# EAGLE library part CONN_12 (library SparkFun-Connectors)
Multi connection point. Often used as Generic Header-pin footprint for 0.1 inch spaced/style header connections On any of the 0.1 inch spaced packages, you can populate with these: Break Away Headers - Straight (PRT-00116) Break Away Male Headers - Right Angle (PRT-00553) Female Headers (PRT-00115) Break Away Headers - Machine Pin (PRT-00117) Break Away Female Headers - Swiss Machine Pin (PRT-00743) For SCREWTERMINALS and SPRING TERMINALS visit here: Screw Terimnals on SparkFun.com (5mm/3.5mm/2.54mm spacing) This device is also useful as a general connection point to wire up your design to another part of your project. Our various solder wires solder well into these plated through hole pads. Hook-Up Wire - Assortment (Stranded, 22 AWG) (PRT-11375) Hook-Up Wire - Assortment (Solid Core, 22 AWG) (PRT-11367) View the entire wire category on our website here Special notes: Molex polarized connector foot print use with SKU : PRT-08231 with associated crimp pins and housings. 1MM SMD Version SKU: PRT-10208 NOTES ON THE VARIANTS LOCK and LOCK_LONGPADS... This footprint was designed to help hold the alignment of a through-hole component (i.e. 6-pin header) while soldering it into place. You may notice that each hole has been shifted either up or down by 0.005 of an inch from it's more standard position (which is a perfectly straight line). This slight alteration caused the pins (the squares in the middle) to touch the edges of the holes. Because they are alternating, it causes a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

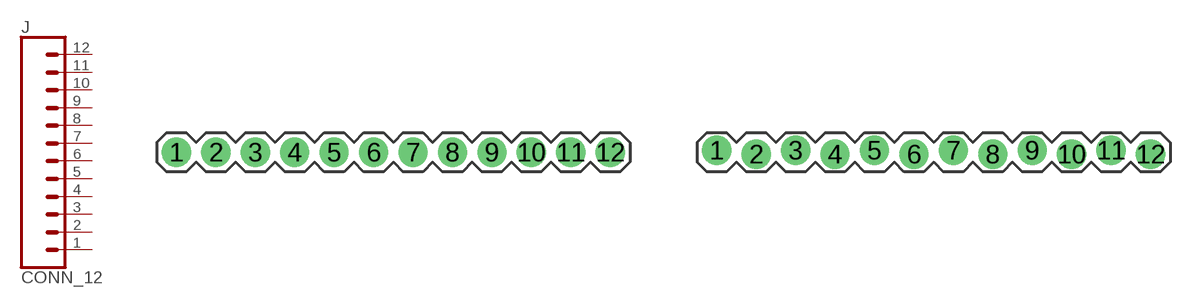
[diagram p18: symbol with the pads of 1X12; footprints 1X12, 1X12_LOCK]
Designator prefix J

## CONN_12  [1X12]
1  1  pas
2  2  pas
3  3  pas
4  4  pas
5  5  pas
6  6  pas
7  7  pas
8  8  pas
9  9  pas
10  10  pas
11  11  pas
12  12  pas

## CONN_12LOCK  [1X12_LOCK]
Pads as for 1X12

## CONN_12LOCK_LONGPADS  [1X12_LOCK_LONGPADS]
Pads as for 1X12

## CONN_12MACHINE-PIN_LOCK (PROD_ID: CONN-09704)  [1X12_MACHINE-PIN-HEADER_LOCK.004]
Pads as for 1X12

## CONN_12LONGPADS  [1X12_LONGPADS]
Pads as for 1X12

## CONN_12POGOPIN_HOLES_ONLY  [1X12_HOLES_ONLY]
Pads as for 1X12

## CONN_121X12_NO_SILK_KIT  [1X12_NO_SILK_KIT]
Pads as for 1X12

## CONN_12NO_SILK  [1X12_NO_SILK]
Pads as for 1X12

## CONN_12LOCK_NO_SILK  [1X12_LOCK_NO_SILK]
Pads as for 1X12

## CONN_12SM_SQ_NO_SILK  [1X12_SM_SQ_NOSILK]
Pads as for 1X12

## CONN_12CASTELLATED  [1X12_CASTELLATED]
1  1  pas
1B  1  pas
2  2  pas
2B  2  pas
3  3  pas
3B  3  pas
4  4  pas
4B  4  pas
5  5  pas
5B  5  pas
6  6  pas
6B  6  pas
7  7  pas
7B  7  pas
8  8  pas
8B  8  pas
9  9  pas
9B  9  pas
10  10  pas
10B  10  pas
11  11  pas
11B  11  pas
12  12  pas
12B  12  pas

## CONN_12SMD (PROD_ID: CONN-15197)  [1X12_SMD]
Pads as for 1X12

## CONN_12SMD_ALT (PROD_ID: CONN-15197)  [1X12_SMD_ALT]
Pads as for 1X12

## CONN_12SMD_COMBINED (PROD_ID: CONN-15197)  [1X12_SMD_COMBINED]
Pads as for 1X12

## CONN_12SMD_COMNINED_NC (PROD_ID: CONN-15197)  [1X12_SMD_COMBINED_NC]
1  1  pas
1@2  1  pas
2  2  pas
2@2  2  pas
3  3  pas
3@2  3  pas
4  4  pas
4@2  4  pas
5  5  pas
5@2  5  pas
6  6  pas
6@2  6  pas
7  7  pas
7@2  7  pas
8  8  pas
8@2  8  pas
9  9  pas
9@2  9  pas
10  10  pas
10@2  10  pas
11  11  pas
11@2  11  pas
12  12  pas
12@2  12  pas

## CONN_12SMD_MALE  [1X12_SMD_MALE]
Pads as for 1X12

## CONN_12FPC_12_0.5MM (PROD_ID: CONN-15766)  [FPC_12_0.5MM]
Pads as for 1X12

## Footprint 1X12 (pad centres in mm)
Plated Through Hole -12 Pin Specifications: Pin count:12 Pin pitch:0.1" Example device(s): CONN_12
drill 1.016 pad 1.88: 1 0,0; 2 2.54,0; 3 5.08,0; 4 7.62,0; 5 10.16,0; 6 12.7,0; 7 15.24,0; 8 17.78,0; 9 20.32,0; 10 22.86,0; 11 25.4,0; 12 27.94,0

## Footprint 1X12_LOCK (pad centres in mm)
Plated Through Hole -12 Pin Locking Footprint Holes are offset 0.005", to hold pins in place during soldering. Specifications: Pin count:12 Pin pitch:0.1" Example device(s): CONN_12
drill 1.016 pad 1.88: 1 0,0.127; 2 2.54,-0.127; 3 5.08,0.127; 4 7.62,-0.127; 5 10.16,0.127; 6 12.7,-0.127; 7 15.24,0.127; 8 17.78,-0.127; 9 20.32,0.127; 10 22.86,-0.127; 11 25.4,0.127; 12 27.94,-0.127

## Footprint 1X12_LOCK_LONGPADS (pad centres in mm)
Plated Through Hole -12 Pin Locking Footprint with Long Pads Holes are offset 0.005", to hold pins in place during soldering. Specifications: Pin count:12 Pin pitch:0.1" Example device(s): CONN_12
drill 1.016 long: 1 0,0.127; 2 2.54,-0.127; 3 5.08,0.127; 4 7.62,-0.127; 5 10.16,0.127; 6 12.7,-0.127; 7 15.24,0.127; 8 17.78,-0.127; 9 20.32,0.127; 10 22.86,-0.127; 11 25.4,0.127; 12 27.94,-0.127

## Footprint 1X12_MACHINE-PIN-HEADER_LOCK.004 (pad centres in mm)
Plated Through Hole -12 Pin Machine Pin Headers Holes are offset 0.005", to hold pins in place during soldering. Specifications: Pin count:12 Pin pitch:0.1" Example device(s): CONN_12
drill 0.889 pad 1.88: 1 0,0.102; 2 2.54,-0.102; 3 5.08,0.102; 4 7.62,-0.102; 5 10.16,0.102; 6 12.7,-0.102; 7 15.24,0.102; 8 17.78,-0.102; 9 20.32,0.102; 10 22.86,-0.102; 11 25.4,0.102; 12 27.94,-0.102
